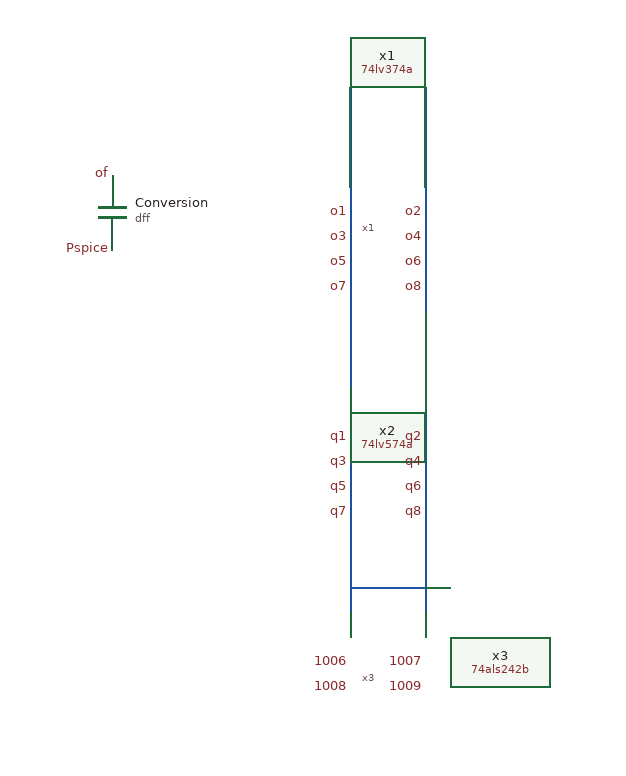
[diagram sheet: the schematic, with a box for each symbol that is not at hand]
v {xschem version=3.4.5 file_version=1.2}
G {}
K {}
V {}
S {}
E {}
C {devices/capa.sym} 440 -280 0 0 {name=Conversion
value=dff}
C {74lv374a.sym} 660 -300 0 0 {name=x1}
C {74lv574a.sym} 660 -120 0 0 {name=x2}
C {74als242b.sym} 660 60 0 0 {name=x3}
T {x1} 640 -280 0 0 0.25 0.25 {}
T {x2} 640 -100 0 0 0.25 0.25 {}
T {x3} 640 80 0 0 0.25 0.25 {}
N 630 -380 630 -200 {lab=oeb}
N 630 -200 630 20 {lab=oeb}
N 630 20 690 20 {lab=oeb}
N 690 -380 690 -200 {lab=clk}
N 630 -360 630 -180 {lab=1in}
N 630 -180 630 40 {lab=1in}
N 690 -360 690 -180 {lab=2in}
N 690 -180 690 40 {lab=2in}
N 630 -340 630 -160 {lab=3in}
N 630 -160 630 60 {lab=3in}
N 690 -340 690 -160 {lab=4in}
N 690 -160 690 60 {lab=4in}
N 630 -320 630 -140 {lab=5in}
N 690 -320 690 -140 {lab=6in}
N 630 -300 630 -120 {lab=7in}
N 690 -300 690 -120 {lab=8in}
C {devices/lab_pin.sym} 440 -310 0 0 {name=l_of sig_type=std_logic lab=of}
C {devices/lab_pin.sym} 440 -250 0 0 {name=l_Pspice sig_type=std_logic lab=Pspice}
C {devices/lab_pin.sym} 630 -280 0 0 {name=l_o1 sig_type=std_logic lab=o1}
C {devices/lab_pin.sym} 690 -280 0 0 {name=l_o2 sig_type=std_logic lab=o2}
C {devices/lab_pin.sym} 630 -260 0 0 {name=l_o3 sig_type=std_logic lab=o3}
C {devices/lab_pin.sym} 690 -260 0 0 {name=l_o4 sig_type=std_logic lab=o4}
C {devices/lab_pin.sym} 630 -240 0 0 {name=l_o5 sig_type=std_logic lab=o5}
C {devices/lab_pin.sym} 690 -240 0 0 {name=l_o6 sig_type=std_logic lab=o6}
C {devices/lab_pin.sym} 630 -220 0 0 {name=l_o7 sig_type=std_logic lab=o7}
C {devices/lab_pin.sym} 690 -220 0 0 {name=l_o8 sig_type=std_logic lab=o8}
C {devices/lab_pin.sym} 630 -100 0 0 {name=l_q1 sig_type=std_logic lab=q1}
C {devices/lab_pin.sym} 690 -100 0 0 {name=l_q2 sig_type=std_logic lab=q2}
C {devices/lab_pin.sym} 630 -80 0 0 {name=l_q3 sig_type=std_logic lab=q3}
C {devices/lab_pin.sym} 690 -80 0 0 {name=l_q4 sig_type=std_logic lab=q4}
C {devices/lab_pin.sym} 630 -60 0 0 {name=l_q5 sig_type=std_logic lab=q5}
C {devices/lab_pin.sym} 690 -60 0 0 {name=l_q6 sig_type=std_logic lab=q6}
C {devices/lab_pin.sym} 630 -40 0 0 {name=l_q7 sig_type=std_logic lab=q7}
C {devices/lab_pin.sym} 690 -40 0 0 {name=l_q8 sig_type=std_logic lab=q8}
C {devices/lab_pin.sym} 630 80 0 0 {name=l_1006 sig_type=std_logic lab=1006}
C {devices/lab_pin.sym} 690 80 0 0 {name=l_1007 sig_type=std_logic lab=1007}
C {devices/lab_pin.sym} 630 100 0 0 {name=l_1008 sig_type=std_logic lab=1008}
C {devices/lab_pin.sym} 690 100 0 0 {name=l_1009 sig_type=std_logic lab=1009}
